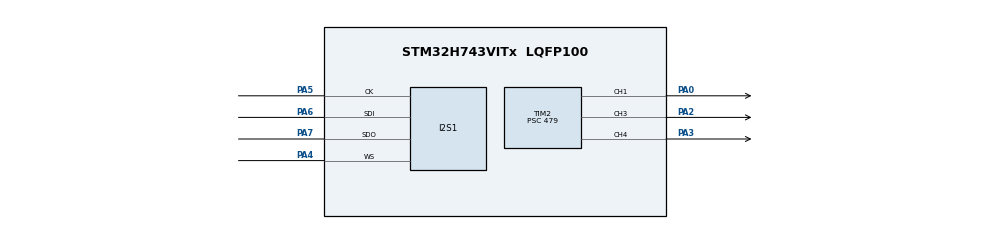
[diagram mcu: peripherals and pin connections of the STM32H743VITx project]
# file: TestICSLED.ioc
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CORTEX_M7.default_mode_Activation=1
Dma.Request0=SPI1_RX
Dma.SPI1_RX.0.Direction=DMA_PERIPH_TO_MEMORY
Dma.SPI1_RX.0.EventEnable=DISABLE
Dma.SPI1_RX.0.FIFOMode=DMA_FIFOMODE_DISABLE
Dma.SPI1_RX.0.Instance=DMA1_Stream0
Dma.SPI1_RX.0.MemDataAlignment=DMA_MDATAALIGN_HALFWORD
Dma.SPI1_RX.0.MemInc=DMA_MINC_ENABLE
Dma.SPI1_RX.0.Mode=DMA_CIRCULAR
Dma.SPI1_RX.0.PeriphDataAlignment=DMA_PDATAALIGN_HALFWORD
Dma.SPI1_RX.0.PeriphInc=DMA_PINC_DISABLE
Dma.SPI1_RX.0.Polarity=HAL_DMAMUX_REQ_GEN_RISING
Dma.SPI1_RX.0.Priority=DMA_PRIORITY_LOW
Dma.SPI1_RX.0.RequestNumber=1
Dma.SPI1_RX.0.SignalID=NONE
Dma.SPI1_RX.0.SyncEnable=DISABLE
Dma.SPI1_RX.0.SyncPolarity=HAL_DMAMUX_SYNC_NO_EVENT
Dma.SPI1_RX.0.SyncRequestNumber=1
Dma.SPI1_RX.0.SyncSignalID=NONE
I2S1.ErrorAudioFreq=-0.27 %
I2S1.Instance=SPI$Index
I2S1.RealAudioFreq=7.978 KHz
Mcu.Family=STM32H7
Mcu.Name=STM32H743VITx
Mcu.Package=LQFP100
NVIC.DMA1_Stream0_IRQn=true\:0\:0\:false\:false\:true\:false\:true\:true
NVIC.PriorityGroup=NVIC_PRIORITYGROUP_4
PA0.Signal=S_TIM2_CH1_ETR
PA2.Signal=S_TIM2_CH3
PA3.Signal=S_TIM2_CH4
PA4.Mode=Full_Duplex_Master
PA4.Signal=I2S1_WS
PA5.Mode=Full_Duplex_Master
PA5.Signal=I2S1_CK
PA6.Mode=Full_Duplex_Master
PA6.Signal=I2S1_SDI
PA7.Mode=Full_Duplex_Master
PA7.Signal=I2S1_SDO
PH0-OSC_IN\ (PH0).Mode=HSE-External-Oscillator
PH0-OSC_IN\ (PH0).Signal=RCC_OSC_IN
PH1-OSC_OUT\ (PH1).Mode=HSE-External-Oscillator
PH1-OSC_OUT\ (PH1).Signal=RCC_OSC_OUT
ProjectManager.HeapSize=0x200
ProjectManager.StackSize=0x400
ProjectManager.TargetToolchain=STM32CubeIDE
RCC.ADCFreq_Value=52406250
RCC.APB1Freq_Value=120000000
RCC.APB2Freq_Value=120000000
RCC.APB3Freq_Value=120000000
RCC.APB4Freq_Value=120000000
RCC.CortexFreq_Value=480000000
RCC.D1PPRE=RCC_APB3_DIV2
RCC.D2PPRE1=RCC_APB1_DIV2
RCC.D2PPRE2=RCC_APB2_DIV2
RCC.D3PPRE=RCC_APB4_DIV2
RCC.DIVM1=13
RCC.DIVN1=480
RCC.DIVQ1=20
RCC.HCLKFreq_Value=240000000
RCC.HPRE=RCC_HCLK_DIV2
RCC.HSE_VALUE=26000000
RCC.PLLFRACN=0
RCC.PLLSourceVirtual=RCC_PLLSOURCE_HSE
RCC.SYSCLKFreq_VALUE=480000000
RCC.SYSCLKSource=RCC_SYSCLKSOURCE_PLLCLK
RCC.USBFreq_Value=48000000
SH.S_TIM2_CH1_ETR.0=TIM2_CH1,PWM Generation1 CH1
SH.S_TIM2_CH3.0=TIM2_CH3,PWM Generation3 CH3
SH.S_TIM2_CH4.0=TIM2_CH4,Output Compare4 CH4
TIM2.Channel-Output\ Compare4\ CH4=TIM_CHANNEL_4
TIM2.Channel-PWM\ Generation1\ CH1=TIM_CHANNEL_1
TIM2.Channel-PWM\ Generation3\ CH3=TIM_CHANNEL_3
TIM2.Prescaler=479
VP_MEMORYMAP_VS_MEMORYMAP.Mode=CurAppReg
board=custom

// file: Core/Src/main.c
/* USER CODE BEGIN Header */
/*
  ******************************************************************************
  * @file           : main.c
  * @brief          : Main program body
  ******************************************************************************
  * @attention
  *
  * Copyright (c) 2025 STMicroelectronics.
  * All rights reserved.
  *
  * This software is licensed under terms that can be found in the LICENSE file
  * in the root directory of this software component.
  * If no LICENSE file comes with this software, it is provided AS-IS.
  *
  ******************************************************************************
  */
/* USER CODE END Header */
#include "main.h"
#include <stdlib.h>

I2S_HandleTypeDef hi2s1;
DMA_HandleTypeDef hdma_spi1_rx;

TIM_HandleTypeDef htim2;

/* USER CODE BEGIN PV */
#define AUDIO_BUFFER_SIZE 512
int16_t audio_buffer[AUDIO_BUFFER_SIZE];

uint32_t audio_level = 0;
/* USER CODE END PV */

void SystemClock_Config(void);
static void MPU_Config(void);
static void MX_GPIO_Init(void);
static void MX_DMA_Init(void);
static void MX_I2S1_Init(void);
static void MX_TIM2_Init(void);

/*
  * @brief  The application entry point.
  * @retval int
  */
int main(void)
{

  /* MPU Configuration--------------------------------------------------------*/
  MPU_Config();

  /* MCU Configuration--------------------------------------------------------*/

  /* Reset of all peripherals, Initializes the Flash interface and the Systick. */
  HAL_Init();

  /* Configure the system clock */
  SystemClock_Config();

  /* Initialize all configured peripherals */
  MX_GPIO_Init();
  MX_DMA_Init();
  MX_I2S1_Init();
  MX_TIM2_Init();
  /* USER CODE BEGIN 2 */
  HAL_TIM_PWM_Start(&htim2, TIM_CHANNEL_1);
  HAL_TIM_PWM_Start(&htim2, TIM_CHANNEL_3);
  HAL_TIM_PWM_Start(&htim2, TIM_CHANNEL_4);

  if (HAL_I2S_Receive_DMA(&hi2s1, (uint16_t *)audio_buffer, AUDIO_BUFFER_SIZE) != HAL_OK)
  {
      Error_Handler();
  }
  /* USER CODE END 2 */

  /* Infinite loop */
  /* USER CODE BEGIN WHILE */
  /* USER CODE BEGIN WHILE */
  while (1)
  {
      // ---- Đổi kênh SEL ----

      // ---- Tính mức âm thanh ----
      uint64_t sum = 0;
      for (int i = 0; i < AUDIO_BUFFER_SIZE; i++)
          sum += abs(audio_buffer[i]);
      audio_level = sum / AUDIO_BUFFER_SIZE;

      if (audio_level > 1000) audio_level = 1000;
// ---- LED RGB theo mức âm ----
      if (audio_level < 10)
      {
          __HAL_TIM_SET_COMPARE(&htim2, TIM_CHANNEL_1, 0);
          __HAL_TIM_SET_COMPARE(&htim2, TIM_CHANNEL_3, 0);
          __HAL_TIM_SET_COMPARE(&htim2, TIM_CHANNEL_4, audio_level);
      }
      else if (audio_level < 100)
      {
          __HAL_TIM_SET_COMPARE(&htim2, TIM_CHANNEL_1, audio_level / 2);
          __HAL_TIM_SET_COMPARE(&htim2, TIM_CHANNEL_3, 0);
          __HAL_TIM_SET_COMPARE(&htim2, TIM_CHANNEL_4, audio_level / 2);
      }
      else
      {
          __HAL_TIM_SET_COMPARE(&htim2, TIM_CHANNEL_1, audio_level);
          __HAL_TIM_SET_COMPARE(&htim2, TIM_CHANNEL_3, 0);
          __HAL_TIM_SET_COMPARE(&htim2, TIM_CHANNEL_4, 0);
      }

      HAL_Delay(50);
  }

  /* USER CODE END WHILE */

  /* USER CODE END 3 */
}

/*
  * @brief System Clock Configuration
  * @retval None
  */
void SystemClock_Config(void)
{
  RCC_OscInitTypeDef RCC_OscInitStruct = {0};
  RCC_ClkInitTypeDef RCC_ClkInitStruct = {0};

  /* Supply configuration update enable
  */
  HAL_PWREx_ConfigSupply(PWR_LDO_SUPPLY);

  /* Configure the main internal regulator output voltage
  */
  __HAL_PWR_VOLTAGESCALING_CONFIG(PWR_REGULATOR_VOLTAGE_SCALE3);

  while(!__HAL_PWR_GET_FLAG(PWR_FLAG_VOSRDY)) {}

  /* Initializes the RCC Oscillators according to the specified parameters
  * in the RCC_OscInitTypeDef structure.
  */
  RCC_OscInitStruct.OscillatorType = RCC_OSCILLATORTYPE_HSE;
  RCC_OscInitStruct.HSEState = RCC_HSE_ON;
  RCC_OscInitStruct.PLL.PLLState = RCC_PLL_ON;
  RCC_OscInitStruct.PLL.PLLSource = RCC_PLLSOURCE_HSE;
  RCC_OscInitStruct.PLL.PLLM = 2;
  RCC_OscInitStruct.PLL.PLLN = 12;
  RCC_OscInitStruct.PLL.PLLP = 2;
  RCC_OscInitStruct.PLL.PLLQ = 2;
  RCC_OscInitStruct.PLL.PLLR = 2;
  RCC_OscInitStruct.PLL.PLLRGE = RCC_PLL1VCIRANGE_3;
  RCC_OscInitStruct.PLL.PLLVCOSEL = RCC_PLL1VCOMEDIUM;
  RCC_OscInitStruct.PLL.PLLFRACN = 0;
  if (HAL_RCC_OscConfig(&RCC_OscInitStruct) != HAL_OK)
  {
    Error_Handler();
  }

  /* Initializes the CPU, AHB and APB buses clocks
  */
  RCC_ClkInitStruct.ClockType = RCC_CLOCKTYPE_HCLK|RCC_CLOCKTYPE_SYSCLK
                              |RCC_CLOCKTYPE_PCLK1|RCC_CLOCKTYPE_PCLK2
                              |RCC_CLOCKTYPE_D3PCLK1|RCC_CLOCKTYPE_D1PCLK1;
  RCC_ClkInitStruct.SYSCLKSource = RCC_SYSCLKSOURCE_HSE;
  RCC_ClkInitStruct.SYSCLKDivider = RCC_SYSCLK_DIV1;
  RCC_ClkInitStruct.AHBCLKDivider = RCC_HCLK_DIV1;
  RCC_ClkInitStruct.APB3CLKDivider = RCC_APB3_DIV1;
  RCC_ClkInitStruct.APB1CLKDivider = RCC_APB1_DIV1;
  RCC_ClkInitStruct.APB2CLKDivider = RCC_APB2_DIV1;
  RCC_ClkInitStruct.APB4CLKDivider = RCC_APB4_DIV1;

  if (HAL_RCC_ClockConfig(&RCC_ClkInitStruct, FLASH_LATENCY_0) != HAL_OK)
  {
    Error_Handler();
  }
}

/*
  * @brief I2S1 Initialization Function
  * @param None
  * @retval None
  */
static void MX_I2S1_Init(void)
{

  hi2s1.Instance = SPI1;
  hi2s1.Init.Mode = I2S_MODE_MASTER_RX;
  hi2s1.Init.Standard = I2S_STANDARD_PHILIPS;
  hi2s1.Init.DataFormat = I2S_DATAFORMAT_16B;
  hi2s1.Init.MCLKOutput = I2S_MCLKOUTPUT_DISABLE;
  hi2s1.Init.AudioFreq = I2S_AUDIOFREQ_48K;
  hi2s1.Init.CPOL = I2S_CPOL_LOW;
  hi2s1.Init.FirstBit = I2S_FIRSTBIT_MSB;
  hi2s1.Init.WSInversion = I2S_WS_INVERSION_DISABLE;
  hi2s1.Init.Data24BitAlignment = I2S_DATA_24BIT_ALIGNMENT_RIGHT;
  hi2s1.Init.MasterKeepIOState = I2S_MASTER_KEEP_IO_STATE_DISABLE;
  if (HAL_I2S_Init(&hi2s1) != HAL_OK)
  {
    Error_Handler();
  }

}

/*
  * @brief TIM2 Initialization Function
  * @param None
  * @retval None
  */
static void MX_TIM2_Init(void)
{

  TIM_MasterConfigTypeDef sMasterConfig = {0};
  TIM_OC_InitTypeDef sConfigOC = {0};

  htim2.Instance = TIM2;
  htim2.Init.Prescaler = 480-1;
  htim2.Init.CounterMode = TIM_COUNTERMODE_UP;
  htim2.Init.Period = 1000;
  htim2.Init.ClockDivision = TIM_CLOCKDIVISION_DIV1;
  htim2.Init.AutoReloadPreload = TIM_AUTORELOAD_PRELOAD_DISABLE;
  if (HAL_TIM_PWM_Init(&htim2) != HAL_OK)
  {
    Error_Handler();
  }
  sMasterConfig.MasterOutputTrigger = TIM_TRGO_RESET;
  sMasterConfig.MasterSlaveMode = TIM_MASTERSLAVEMODE_DISABLE;
  if (HAL_TIMEx_MasterConfigSynchronization(&htim2, &sMasterConfig) != HAL_OK)
  {
    Error_Handler();
  }
  sConfigOC.OCMode = TIM_OCMODE_PWM1;
  sConfigOC.Pulse = 0;
  sConfigOC.OCPolarity = TIM_OCPOLARITY_HIGH;
  sConfigOC.OCFastMode = TIM_OCFAST_DISABLE;
  if (HAL_TIM_PWM_ConfigChannel(&htim2, &sConfigOC, TIM_CHANNEL_1) != HAL_OK)
  {
    Error_Handler();
  }
  if (HAL_TIM_PWM_ConfigChannel(&htim2, &sConfigOC, TIM_CHANNEL_3) != HAL_OK)
  {
    Error_Handler();
  }
  if (HAL_TIM_PWM_ConfigChannel(&htim2, &sConfigOC, TIM_CHANNEL_4) != HAL_OK)
  {
    Error_Handler();
  }
  HAL_TIM_MspPostInit(&htim2);

}

/*
  * Enable DMA controller clock
  */
static void MX_DMA_Init(void)
{

  /* DMA controller clock enable */
  __HAL_RCC_DMA1_CLK_ENABLE();

  /* DMA interrupt init */
  /* DMA1_Stream0_IRQn interrupt configuration */
  HAL_NVIC_SetPriority(DMA1_Stream0_IRQn, 0, 0);
  HAL_NVIC_EnableIRQ(DMA1_Stream0_IRQn);

}

/*
  * @brief GPIO Initialization Function
  * @param None
  * @retval None
  */
static void MX_GPIO_Init(void)
{

  /* GPIO Ports Clock Enable */
  __HAL_RCC_GPIOH_CLK_ENABLE();
  __HAL_RCC_GPIOA_CLK_ENABLE();
  __HAL_RCC_GPIOC_CLK_ENABLE();
  __HAL_RCC_GPIOD_CLK_ENABLE();

}

 /* MPU Configuration */

void MPU_Config(void)
{
  MPU_Region_InitTypeDef MPU_InitStruct = {0};

  /* Disables the MPU */
  HAL_MPU_Disable();
/* Initializes and configures the Region and the memory to be protected
  */
  MPU_InitStruct.Enable = MPU_REGION_ENABLE;
  MPU_InitStruct.Number = MPU_REGION_NUMBER0;
  MPU_InitStruct.BaseAddress = 0x0;
  MPU_InitStruct.Size = MPU_REGION_SIZE_4GB;
  MPU_InitStruct.SubRegionDisable = 0x87;
  MPU_InitStruct.TypeExtField = MPU_TEX_LEVEL0;
  MPU_InitStruct.AccessPermission = MPU_REGION_NO_ACCESS;
  MPU_InitStruct.DisableExec = MPU_INSTRUCTION_ACCESS_DISABLE;
  MPU_InitStruct.IsShareable = MPU_ACCESS_SHAREABLE;
  MPU_InitStruct.IsCacheable = MPU_ACCESS_NOT_CACHEABLE;
  MPU_InitStruct.IsBufferable = MPU_ACCESS_NOT_BUFFERABLE;

  HAL_MPU_ConfigRegion(&MPU_InitStruct);
  /* Enables the MPU */
  HAL_MPU_Enable(MPU_PRIVILEGED_DEFAULT);

}

/*
  * @brief  This function is executed in case of error occurrence.
  * @retval None
  */
void Error_Handler(void)
{
  __disable_irq();
  while (1)
  {
  }
}
